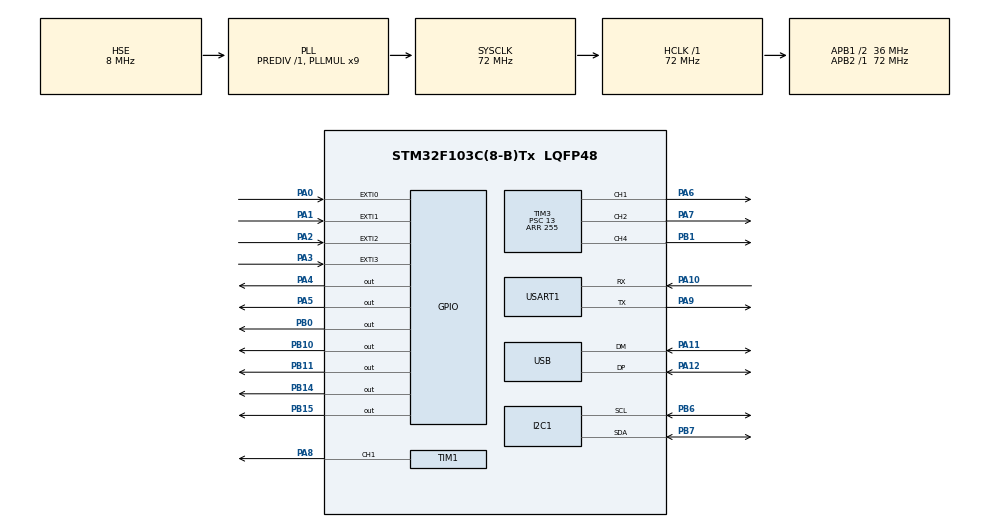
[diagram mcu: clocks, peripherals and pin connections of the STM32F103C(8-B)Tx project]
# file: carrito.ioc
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Mcu.Family=STM32F1
Mcu.Name=STM32F103C(8-B)Tx
Mcu.Package=LQFP48
NVIC.EXTI0_IRQn=true\:0\:0\:false\:false\:true\:true\:true
NVIC.EXTI1_IRQn=true\:0\:0\:false\:false\:true\:true\:true
NVIC.EXTI2_IRQn=true\:0\:0\:false\:false\:true\:true\:true
NVIC.EXTI3_IRQn=true\:0\:0\:false\:false\:true\:true\:true
NVIC.PriorityGroup=NVIC_PRIORITYGROUP_4
NVIC.USB_LP_CAN1_RX0_IRQn=true\:0\:0\:false\:false\:true\:false\:true
PA0-WKUP.Signal=GPXTI0
PA1.Signal=GPXTI1
PA10.Mode=Asynchronous
PA10.Signal=USART1_RX
PA11.Mode=Device
PA11.Signal=USB_DM
PA12.Mode=Device
PA12.Signal=USB_DP
PA13.Mode=Serial_Wire
PA13.Signal=SYS_JTMS-SWDIO
PA14.Mode=Serial_Wire
PA14.Signal=SYS_JTCK-SWCLK
PA2.Signal=GPXTI2
PA3.Signal=GPXTI3
PA4.Signal=GPIO_Output
PA5.Signal=GPIO_Output
PA6.Signal=S_TIM3_CH1
PA7.Signal=S_TIM3_CH2
PA8.Signal=S_TIM1_CH1
PA9.Mode=Asynchronous
PA9.Signal=USART1_TX
PB0.Signal=GPIO_Output
PB1.Signal=S_TIM3_CH4
PB10.Signal=GPIO_Output
PB11.Signal=GPIO_Output
PB14.Signal=GPIO_Output
PB15.Signal=GPIO_Output
PB6.Mode=I2C
PB6.Signal=I2C1_SCL
PB7.Mode=I2C
PB7.Signal=I2C1_SDA
PC14-OSC32_IN.Mode=LSE-External-Oscillator
PC14-OSC32_IN.Signal=RCC_OSC32_IN
PC15-OSC32_OUT.Mode=LSE-External-Oscillator
PC15-OSC32_OUT.Signal=RCC_OSC32_OUT
PD0-OSC_IN.Mode=HSE-External-Oscillator
PD0-OSC_IN.Signal=RCC_OSC_IN
PD1-OSC_OUT.Mode=HSE-External-Oscillator
PD1-OSC_OUT.Signal=RCC_OSC_OUT
ProjectManager.HeapSize=0x200
ProjectManager.StackSize=0x400
ProjectManager.TargetToolchain=STM32CubeIDE
RCC.AHBFreq_Value=72000000
RCC.APB1CLKDivider=RCC_HCLK_DIV2
RCC.APB1Freq_Value=36000000
RCC.APB1TimFreq_Value=72000000
RCC.APB2Freq_Value=72000000
RCC.APB2TimFreq_Value=72000000
RCC.HCLKFreq_Value=72000000
RCC.PLLMUL=RCC_PLL_MUL9
RCC.SYSCLKFreq_VALUE=72000000
RCC.SYSCLKSource=RCC_SYSCLKSOURCE_PLLCLK
RCC.USBFreq_Value=48000000
RCC.USBPrescaler=RCC_USBCLKSOURCE_PLL_DIV1_5
SH.S_TIM1_CH1.0=TIM1_CH1,PWM Generation1 CH1
SH.S_TIM3_CH1.0=TIM3_CH1,PWM Generation1 CH1
SH.S_TIM3_CH2.0=TIM3_CH2,PWM Generation2 CH2
SH.S_TIM3_CH4.0=TIM3_CH4,PWM Generation4 CH4
TIM1.Channel-PWM\ Generation1\ CH1=TIM_CHANNEL_1
TIM1.Period=255
TIM1.Prescaler=13
TIM3.Channel-PWM\ Generation1\ CH1=TIM_CHANNEL_1
TIM3.Channel-PWM\ Generation2\ CH2=TIM_CHANNEL_2
TIM3.Channel-PWM\ Generation4\ CH4=TIM_CHANNEL_4
TIM3.Period=255
TIM3.Prescaler=13
USART1.VirtualMode=VM_ASYNC
USB_DEVICE.CLASS_NAME_FS=CDC
USB_DEVICE.VirtualMode=Cdc
USB_DEVICE.VirtualModeFS=Cdc_FS
VP_USB_DEVICE_VS_USB_DEVICE_CDC_FS.Mode=CDC_FS
board=custom

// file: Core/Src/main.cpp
/* USER CODE BEGIN Header */
/**
 ******************************************************************************
 * @file           : main.c
 * @brief          : Main program body
 ******************************************************************************
 * @attention
 *
 * <h2><center>&copy; Copyright (c) 2025 STMicroelectronics.
 * All rights reserved.</center></h2>
 *
 * This software component is licensed by ST under Ultimate Liberty license
 * SLA0044, the "License"; You may not use this file except in compliance with
 * the License. You may obtain a copy of the License at:
 *                             www.st.com/SLA0044
 *
 ******************************************************************************
 */
/* USER CODE END Header */
#include "main.h"
#include "usb_device.h"
#include <cmath>

/* USER CODE BEGIN Includes */
#include "Constants.h"
#include "Motor.h"
#include "stm32f1xx_hal_tim.h"
#include "Movement.h"
#include "bluetooth_uart.h"

// #include "BNOController.h"

extern "C"
{
#include "lcd.h"
#include "BNOController.h"
}
/* USER CODE END Includes */

I2C_HandleTypeDef hi2c1;
// BNOController bno;
// 22,.9 PARA MINIMA
int speed = 15;
int target = 463;
int square_size = 100;
int current_angle_algorithm = 0;
int a = 1;
bool on_Wait = false;

void SystemClock_Config(void);
static void MX_GPIO_Init(void);
static void MX_I2C1_Init(void);
static void MX_TIM1_Init(void);
static void MX_TIM3_Init(void);
static void MX_USART1_UART_Init(void);

/* USER CODE BEGIN PFP */
void HAL_GPIO_EXTI_Callback(uint16_t GPIO_Pin)
{
  switch (GPIO_Pin)
  {
  case Constants::kFrontLeftEncoder:
    frontLeftMotor.addTicks();
    break;
  case Constants::kFrontRightEncoder:
    frontRightMotor.addTicks();
    break;
  case Constants::kBackLeftEncoder:
    backLeftMotor.addTicks();
    break;
  case Constants::kBackRightEncoder:
    backRightMotor.addTicks();
    break;
  }
}
/* USER CODE END PFP */

/* USER CODE BEGIN 0 */
// PRBS //
bool b1, b2, b6, b9, b11 = false;
bool b5, b3, b7, b8, b4, b10 = true;
void PRBS();

/* USER CODE END 0 */

int main(void)
{

  /* MCU Configuration--------------------------------------------------------*/

  /* Reset of all peripherals, Initializes the Flash interface and the Systick. */
  HAL_Init();

  /* Configure the system clock */
  SystemClock_Config();

  /* Initialize all configured peripherals */
  MX_GPIO_Init();
  MX_I2C1_Init();
  MX_USB_DEVICE_Init();
  MX_TIM1_Init();
  MX_TIM3_Init();
  MX_USART1_UART_Init();

  /* USER CODE BEGIN 2 */
  MX_GPIO_Init();
  MX_I2C1_Init();
  MX_USB_DEVICE_Init();
  /* USER CODE BEGIN 2 */

  HAL_Init();
  SystemClock_Config();
  MX_GPIO_Init();
  MX_TIM1_Init();
  MX_TIM3_Init();

  lcd_begin();
  bno.init();
  send_msg("Equipo4");

  movementInit();

  /// SPEED
  setSpeed(speed);
  // bno.setTargetYaw(90);
  uint32_t last_average_time = 0;
  float total_distance = 0;
  uint32_t last_time_print, last_PIDYAW, dt = HAL_GetTick();
  uint32_t init_time, stop_pls = HAL_GetTick();

  // POS //
  float distancia_entera = 0;
  float delta_x, delta_y = 0;
  float pos_x, pos_y = 0;
  int current_speed = 0;
  float last_size = 0;
  float iteration = 0;

  // frontLeftMotor.set_pwm_forward(153);
  // frontRightMotor.set_pwm_forward(153);
  // backLeftMotor.set_pwm_forward(153);
  // backRightMotor.set_pwm_forward(153);
  /* USER CODE END 2 */

  /* Infinite loop */
  while (1)
  {

    // Timer //
    uint32_t now = HAL_GetTick();
    // updateWithoutPID(now);
    updateMovement(now);

    // PID Updater //

    if (now - last_PIDYAW >= 100)
    {
      setKinematicSpeeds(speed, now);

      // Odometry //
      dt = (now - last_PIDYAW) / 1000.0f;
      delta_x = current_speed * cos(bno.getYawRad()) * dt;
      delta_y = current_speed * sin(bno.getYawRad()) * dt;
      pos_x += delta_x;
      pos_y += delta_y;

      last_PIDYAW = now;
    }

    // Communication Message //
    if (now - last_time_print > 100)
    {

      distancia_entera = ((backLeftMotor.getDistance() + backRightMotor.getDistance() + frontLeftMotor.getDistance() + frontRightMotor.getDistance()) / 4);

      // LCD //
      // char buffer[32];
      // sprintf(buffer, "(%d,  %d)", (int)pos_x, (int)pos_y);
      // lcd_clean();
      // send_msg(buffer);

      // Bluetooth //
      sendMotorSpeeds(distancia_entera, bno.getYaw(), bno.getError());
      // float yaw = bno.getSpeed();
      // sendYaw(yaw);

      last_time_print = now;
      // if (b11)
      // {
      //   setRotation(true);
      // }
      // else
      // {
      //   setRotation(false);
      // }
      // PRBS();
    }

    if (distancia_entera - last_size >= square_size && iteration <= 3)
    {
      on_Wait = true;
      speed = 0;
      setSpeed(speed);
      current_angle_algorithm += 90;
      bno.setTargetYaw(current_angle_algorithm);
      last_size = distancia_entera;
      stop_pls = now;
      iteration++;
    }

    if (on_Wait && !(std::abs(current_angle_algorithm - bno.getYaw()) <= 10))
    {
      stop_pls = now;
      last_size = distancia_entera;
    }

    if (on_Wait && now - stop_pls >= 10000)
    {
      if (iteration <= 3)
      {
        speed = 15;
      }
      else
      {
        speed = 0;
      }

      on_Wait = false;
      setSpeed(speed);
      last_size = distancia_entera;
    }

    // Maquina de Estados //
    //    if (now - init_time > 2000){
    ////      setSpeed(speed);
    //    	frontLeftMotor.set_pwm_forward(255);
    //    	frontRightMotor.set_pwm_forward(255);
    //    	backLeftMotor.set_pwm_forward(255);
    //    	backRightMotor.set_pwm_forward(255);
    //      current_speed = speed;
    //    }

    // Stop after a set condition //
    // while (now - init_time > 20000) // CM por alcanzar
    // {
    //   // float yaw = bno.getYaw();
    //   // sendYaw(yaw);
    //   stop();
    //   // HAL_Delay(Constants::kTimeDelay);
    // }

    HAL_Delay(Constants::kTimeDelay);
  }
}

void SystemClock_Config(void)
{
  RCC_OscInitTypeDef RCC_OscInitStruct = {0};
  RCC_ClkInitTypeDef RCC_ClkInitStruct = {0};
  RCC_PeriphCLKInitTypeDef PeriphClkInit = {0};

  /** Initializes the RCC Oscillators according to the specified parameters
   * in the RCC_OscInitTypeDef structure.
   */
  RCC_OscInitStruct.OscillatorType = RCC_OSCILLATORTYPE_HSE;
  RCC_OscInitStruct.HSEState = RCC_HSE_ON;
  RCC_OscInitStruct.HSEPredivValue = RCC_HSE_PREDIV_DIV1;
  RCC_OscInitStruct.HSIState = RCC_HSI_ON;
  RCC_OscInitStruct.PLL.PLLState = RCC_PLL_ON;
  RCC_OscInitStruct.PLL.PLLSource = RCC_PLLSOURCE_HSE;
  RCC_OscInitStruct.PLL.PLLMUL = RCC_PLL_MUL9;
  if (HAL_RCC_OscConfig(&RCC_OscInitStruct) != HAL_OK)
  {
    Error_Handler();
  }
  /** Initializes the CPU, AHB and APB buses clocks
   */
  RCC_ClkInitStruct.ClockType = RCC_CLOCKTYPE_HCLK | RCC_CLOCKTYPE_SYSCLK | RCC_CLOCKTYPE_PCLK1 | RCC_CLOCKTYPE_PCLK2;
  RCC_ClkInitStruct.SYSCLKSource = RCC_SYSCLKSOURCE_PLLCLK;
  RCC_ClkInitStruct.AHBCLKDivider = RCC_SYSCLK_DIV1;
  RCC_ClkInitStruct.APB1CLKDivider = RCC_HCLK_DIV2;
  RCC_ClkInitStruct.APB2CLKDivider = RCC_HCLK_DIV1;

  if (HAL_RCC_ClockConfig(&RCC_ClkInitStruct, FLASH_LATENCY_2) != HAL_OK)
  {
    Error_Handler();
  }
  PeriphClkInit.PeriphClockSelection = RCC_PERIPHCLK_USB;
  PeriphClkInit.UsbClockSelection = RCC_USBCLKSOURCE_PLL_DIV1_5;
  if (HAL_RCCEx_PeriphCLKConfig(&PeriphClkInit) != HAL_OK)
  {
    Error_Handler();
  }
}

static void MX_I2C1_Init(void)
{

  hi2c1.Instance = I2C1;
  hi2c1.Init.ClockSpeed = 100000;
  hi2c1.Init.DutyCycle = I2C_DUTYCYCLE_2;
  hi2c1.Init.OwnAddress1 = 0;
  hi2c1.Init.AddressingMode = I2C_ADDRESSINGMODE_7BIT;
  hi2c1.Init.DualAddressMode = I2C_DUALADDRESS_DISABLE;
  hi2c1.Init.OwnAddress2 = 0;
  hi2c1.Init.GeneralCallMode = I2C_GENERALCALL_DISABLE;
  hi2c1.Init.NoStretchMode = I2C_NOSTRETCH_DISABLE;
  if (HAL_I2C_Init(&hi2c1) != HAL_OK)
  {
    Error_Handler();
  }
}

static void MX_TIM1_Init(void)
{

  TIM_MasterConfigTypeDef sMasterConfig = {0};
  TIM_OC_InitTypeDef sConfigOC = {0};
  TIM_BreakDeadTimeConfigTypeDef sBreakDeadTimeConfig = {0};

  htim1.Instance = TIM1;
  htim1.Init.Prescaler = 13;
  htim1.Init.CounterMode = TIM_COUNTERMODE_UP;
  htim1.Init.Period = 255;
  htim1.Init.ClockDivision = TIM_CLOCKDIVISION_DIV1;
  htim1.Init.RepetitionCounter = 0;
  htim1.Init.AutoReloadPreload = TIM_AUTORELOAD_PRELOAD_DISABLE;
  if (HAL_TIM_PWM_Init(&htim1) != HAL_OK)
  {
    Error_Handler();
  }
  sMasterConfig.MasterOutputTrigger = TIM_TRGO_RESET;
  sMasterConfig.MasterSlaveMode = TIM_MASTERSLAVEMODE_DISABLE;
  if (HAL_TIMEx_MasterConfigSynchronization(&htim1, &sMasterConfig) != HAL_OK)
  {
    Error_Handler();
  }
  sConfigOC.OCMode = TIM_OCMODE_PWM1;
  sConfigOC.Pulse = 0;
  sConfigOC.OCPolarity = TIM_OCPOLARITY_HIGH;
  sConfigOC.OCNPolarity = TIM_OCNPOLARITY_HIGH;
  sConfigOC.OCFastMode = TIM_OCFAST_DISABLE;
  sConfigOC.OCIdleState = TIM_OCIDLESTATE_RESET;
  sConfigOC.OCNIdleState = TIM_OCNIDLESTATE_RESET;
  if (HAL_TIM_PWM_ConfigChannel(&htim1, &sConfigOC, TIM_CHANNEL_1) != HAL_OK)
  {
    Error_Handler();
  }
  sBreakDeadTimeConfig.OffStateRunMode = TIM_OSSR_DISABLE;
  sBreakDeadTimeConfig.OffStateIDLEMode = TIM_OSSI_DISABLE;
  sBreakDeadTimeConfig.LockLevel = TIM_LOCKLEVEL_OFF;
  sBreakDeadTimeConfig.DeadTime = 0;
  sBreakDeadTimeConfig.BreakState = TIM_BREAK_DISABLE;
  sBreakDeadTimeConfig.BreakPolarity = TIM_BREAKPOLARITY_HIGH;
  sBreakDeadTimeConfig.AutomaticOutput = TIM_AUTOMATICOUTPUT_DISABLE;
  if (HAL_TIMEx_ConfigBreakDeadTime(&htim1, &sBreakDeadTimeConfig) != HAL_OK)
  {
    Error_Handler();
  }
  HAL_TIM_MspPostInit(&htim1);
}

static void MX_TIM3_Init(void)
{

  TIM_MasterConfigTypeDef sMasterConfig = {0};
  TIM_OC_InitTypeDef sConfigOC = {0};

  htim3.Instance = TIM3;
  htim3.Init.Prescaler = 13;
  htim3.Init.CounterMode = TIM_COUNTERMODE_UP;
  htim3.Init.Period = 255;
  htim3.Init.ClockDivision = TIM_CLOCKDIVISION_DIV1;
  htim3.Init.AutoReloadPreload = TIM_AUTORELOAD_PRELOAD_DISABLE;
  if (HAL_TIM_PWM_Init(&htim3) != HAL_OK)
  {
    Error_Handler();
  }
  sMasterConfig.MasterOutputTrigger = TIM_TRGO_RESET;
  sMasterConfig.MasterSlaveMode = TIM_MASTERSLAVEMODE_DISABLE;
  if (HAL_TIMEx_MasterConfigSynchronization(&htim3, &sMasterConfig) != HAL_OK)
  {
    Error_Handler();
  }
  sConfigOC.OCMode = TIM_OCMODE_PWM1;
  sConfigOC.Pulse = 0;
  sConfigOC.OCPolarity = TIM_OCPOLARITY_HIGH;
  sConfigOC.OCFastMode = TIM_OCFAST_DISABLE;
  if (HAL_TIM_PWM_ConfigChannel(&htim3, &sConfigOC, TIM_CHANNEL_1) != HAL_OK)
  {
    Error_Handler();
  }
  if (HAL_TIM_PWM_ConfigChannel(&htim3, &sConfigOC, TIM_CHANNEL_2) != HAL_OK)
  {
    Error_Handler();
  }
  if (HAL_TIM_PWM_ConfigChannel(&htim3, &sConfigOC, TIM_CHANNEL_4) != HAL_OK)
  {
    Error_Handler();
  }
  HAL_TIM_MspPostInit(&htim3);
}

static void MX_USART1_UART_Init(void)
{

  huart1.Instance = USART1;
  huart1.Init.BaudRate = 9600;
  huart1.Init.WordLength = UART_WORDLENGTH_8B;
  huart1.Init.StopBits = UART_STOPBITS_1;
  huart1.Init.Parity = UART_PARITY_NONE;
  huart1.Init.Mode = UART_MODE_TX_RX;
  huart1.Init.HwFlowCtl = UART_HWCONTROL_NONE;
  huart1.Init.OverSampling = UART_OVERSAMPLING_16;
  if (HAL_UART_Init(&huart1) != HAL_OK)
  {
    Error_Handler();
  }
}

static void MX_GPIO_Init(void)
{
  GPIO_InitTypeDef GPIO_InitStruct = {0};

  /* GPIO Ports Clock Enable */
  __HAL_RCC_GPIOC_CLK_ENABLE();
  __HAL_RCC_GPIOD_CLK_ENABLE();
  __HAL_RCC_GPIOA_CLK_ENABLE();
  __HAL_RCC_GPIOB_CLK_ENABLE();

  /*Configure GPIO pin Output Level */
  HAL_GPIO_WritePin(GPIOA, GPIO_PIN_4 | GPIO_PIN_5, GPIO_PIN_RESET);

  /*Configure GPIO pin Output Level */
  HAL_GPIO_WritePin(GPIOB, GPIO_PIN_0 | GPIO_PIN_10 | GPIO_PIN_11 | GPIO_PIN_13 | GPIO_PIN_14 | GPIO_PIN_15, GPIO_PIN_RESET);

  /*Configure GPIO pins : PA0 PA1 PA2 PA3 PA4*/
  GPIO_InitStruct.Pin = GPIO_PIN_0 | GPIO_PIN_1 | GPIO_PIN_2 | GPIO_PIN_3 | GPIO_PIN_4;
  GPIO_InitStruct.Mode = GPIO_MODE_IT_RISING;
  GPIO_InitStruct.Pull = GPIO_PULLUP;
  HAL_GPIO_Init(GPIOA, &GPIO_InitStruct);

  /*Configure GPIO pins : PA4 PA5 */
  GPIO_InitStruct.Pin = GPIO_PIN_4 | GPIO_PIN_5;
  GPIO_InitStruct.Mode = GPIO_MODE_OUTPUT_PP;
  GPIO_InitStruct.Pull = GPIO_NOPULL;
  GPIO_InitStruct.Speed = GPIO_SPEED_FREQ_LOW;
  HAL_GPIO_Init(GPIOA, &GPIO_InitStruct);

  /*Configure GPIO pins : PB0 PB10 PB11 PB12 PB13
                           PB14 PB15 */
  GPIO_InitStruct.Pin = GPIO_PIN_0 | GPIO_PIN_10 | GPIO_PIN_11 | GPIO_PIN_12 | GPIO_PIN_13 | GPIO_PIN_14 | GPIO_PIN_15;
  GPIO_InitStruct.Mode = GPIO_MODE_OUTPUT_PP;
  GPIO_InitStruct.Pull = GPIO_NOPULL;
  GPIO_InitStruct.Speed = GPIO_SPEED_FREQ_LOW;
  HAL_GPIO_Init(GPIOB, &GPIO_InitStruct);

  /* EXTI interrupt init*/
  HAL_NVIC_SetPriority(EXTI0_IRQn, 0, 0);
  HAL_NVIC_EnableIRQ(EXTI0_IRQn);

  HAL_NVIC_SetPriority(EXTI1_IRQn, 0, 0);
  HAL_NVIC_EnableIRQ(EXTI1_IRQn);

  HAL_NVIC_SetPriority(EXTI2_IRQn, 0, 0);
  HAL_NVIC_EnableIRQ(EXTI2_IRQn);

  HAL_NVIC_SetPriority(EXTI3_IRQn, 0, 0);
  HAL_NVIC_EnableIRQ(EXTI3_IRQn);
}

/* USER CODE BEGIN 4 */
void PRBS()
{
  // Tap en b9 y b5 → XOR para retroalimentación
  bool feedback = b11 ^ b9;

  // Shift (de derecha a izquierda: b11 ← b10 ← ... ← b1)
  b11 = b10;
  b10 = b9;
  b9 = b8;
  b8 = b7;
  b7 = b6;
  b6 = b5;
  b5 = b4;
  b4 = b3;
  b3 = b2;
  b2 = b1;
  b1 = feedback; // nuevo bit entra por la izquierda
}
/* USER CODE END 4 */

void Error_Handler(void)
{
  __disable_irq();
  while (1)
  {
  }
}

/************************ (C) COPYRIGHT STMicroelectronics *****END OF FILE****/
